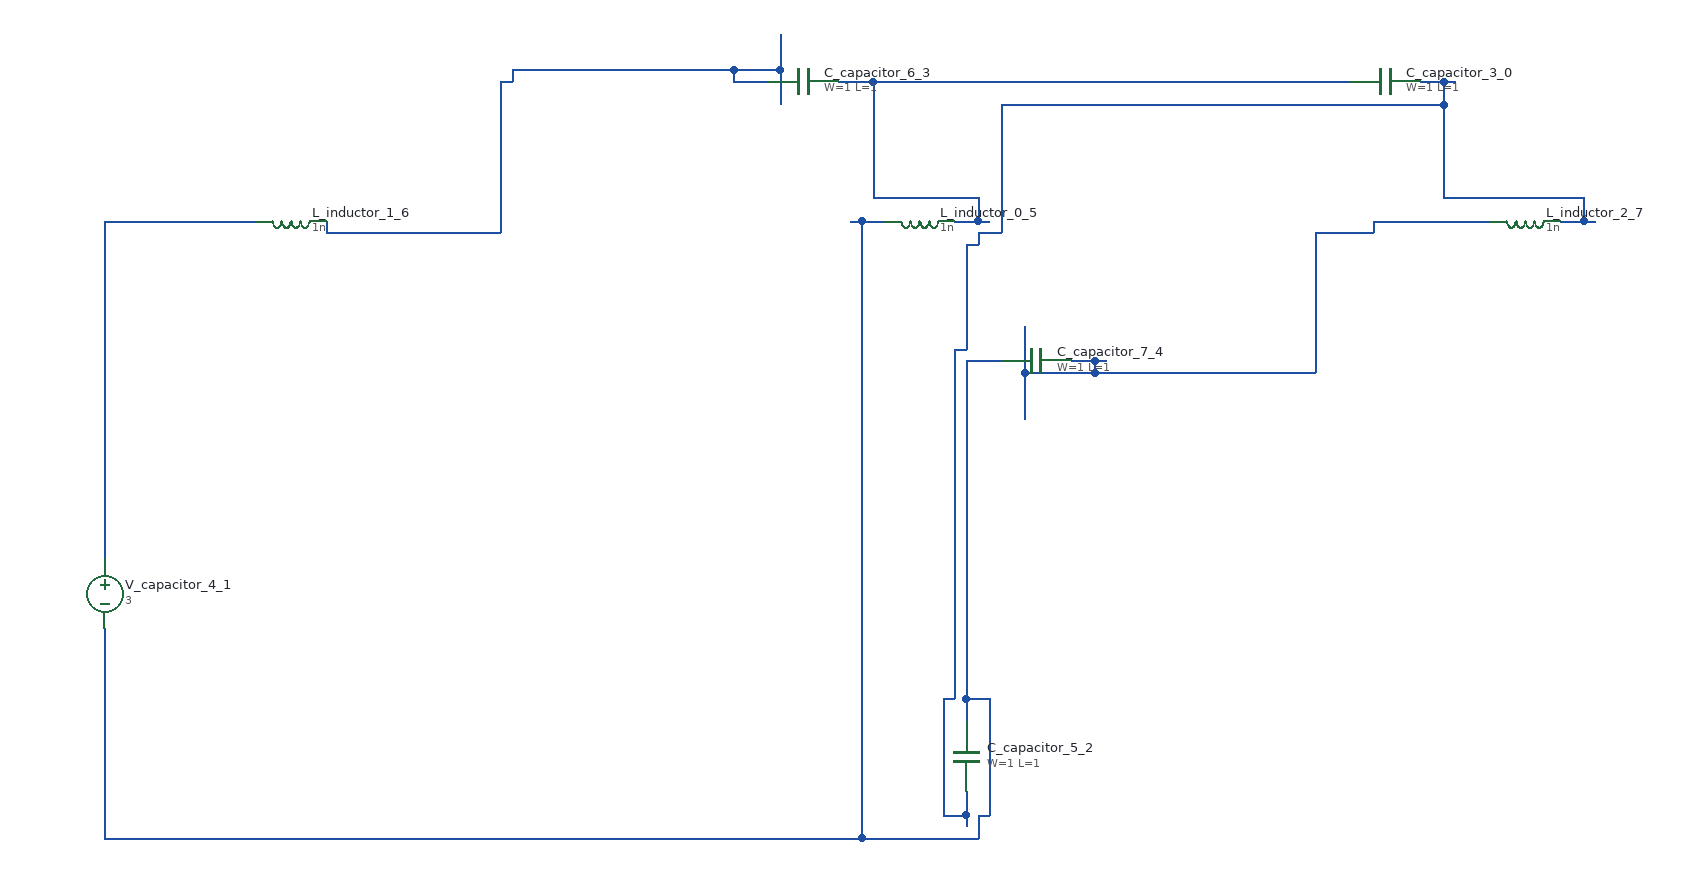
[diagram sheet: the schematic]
v {xschem version=3.4.8 file_version=1.2}
G {}
K {}
V {}
S {}
E {}
C {sky130_fd_pr/cap_mim_m3_1.sym} 1280 180 1 0 {name="C_capacitor_3_0" model=cap_mim_m3_1 W=1 L=1 MF=1 spiceprefix=X}
C {devices/vsource.sym} 180 620 0 0 {name="V_capacitor_4_1" value=3 savecurrent=false}
C {sky130_fd_pr/cap_mim_m3_1.sym} 920 760 0 0 {name="C_capacitor_5_2" model=cap_mim_m3_1 W=1 L=1 MF=1 spiceprefix=X}
C {sky130_fd_pr/cap_mim_m3_1.sym} 780 180 1 0 {name="C_capacitor_6_3" model=cap_mim_m3_1 W=1 L=1 MF=1 spiceprefix=X}
C {sky130_fd_pr/cap_mim_m3_1.sym} 980 420 1 0 {name="C_capacitor_7_4" model=cap_mim_m3_1 W=1 L=1 MF=1 spiceprefix=X}
C {devices/ind.sym} 880 300 1 0 {name="L_inductor_0_5"
m=1
value=1n
footprint=1206
device=inductor}
C {devices/ind.sym} 340 300 1 0 {name="L_inductor_1_6"
m=1
value=1n
footprint=1206
device=inductor}
C {devices/ind.sym} 1400 300 1 0 {name="L_inductor_2_7"
m=1
value=1n
footprint=1206
device=inductor}
N 900 810 920 810 {}
N 900 710 910 710 {}
N 910 410 920 410 {}
N 920 320 930 320 {}
N 930 310 950 310 {}
N 1430 300 1450 300 {}
N 1450 300 1460 300 {}
N 1330 280 1450 280 {}
N 950 200 1330 200 {}
N 1310 180 1330 180 {}
N 1330 180 1340 180 {}
N 900 810 900 710 {}
N 910 710 910 410 {}
N 920 820 920 810 {}
N 920 810 920 790 {}
N 920 410 920 320 {}
N 930 320 930 310 {}
N 950 310 950 200 {}
N 1330 280 1330 200 {}
N 1330 200 1330 180 {}
N 1450 300 1450 280 {}
N 910 300 930 300 {}
N 930 300 940 300 {}
N 840 280 930 280 {}
N 810 180 840 180 {}
N 840 180 1250 180 {}
N 840 280 840 180 {}
N 930 300 930 280 {}
N 970 430 1030 430 {}
N 1030 430 1220 430 {}
N 1010 420 1030 420 {}
N 1030 420 1040 420 {}
N 1220 310 1270 310 {}
N 1270 300 1370 300 {}
N 970 470 970 430 {}
N 970 430 970 390 {}
N 1030 430 1030 420 {}
N 1220 430 1220 310 {}
N 1270 310 1270 300 {}
N 180 300 310 300 {}
N 180 590 180 300 {}
N 180 830 830 830 {}
N 830 830 930 830 {}
N 930 810 940 810 {}
N 920 710 940 710 {}
N 920 420 950 420 {}
N 820 300 830 300 {}
N 830 300 850 300 {}
N 180 830 180 650 {}
N 830 830 830 300 {}
N 920 730 920 710 {}
N 920 710 920 420 {}
N 930 830 930 810 {}
N 940 810 940 710 {}
N 370 310 520 310 {}
N 520 180 530 180 {}
N 720 180 750 180 {}
N 530 170 720 170 {}
N 720 170 760 170 {}
N 370 310 370 300 {}
N 520 310 520 180 {}
N 530 180 530 170 {}
N 720 180 720 170 {}
N 760 200 760 170 {}
N 760 170 760 140 {}
